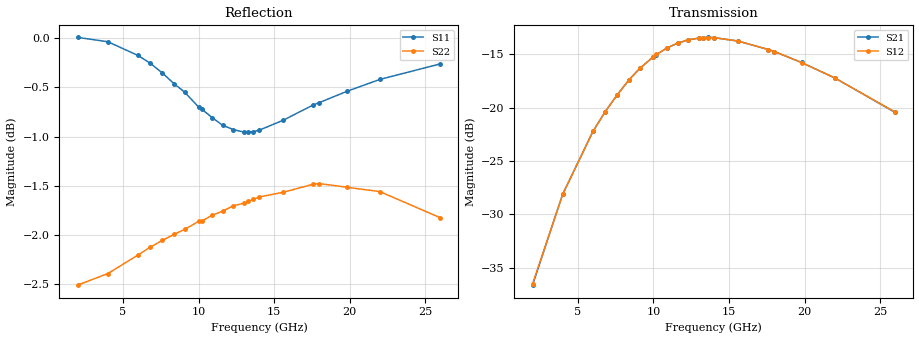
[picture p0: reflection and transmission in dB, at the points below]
! CHUO DENSHI KOGYO Co.,Ltd.
! 1. March 2016
! CKRF7513MM34
! N-channel HJ-FET
! Vds = 0 V Vgs = 0 V
# Hz S  MA  R 50
!  f  S11  S21  S12  S22
!  Hz  MAG  ANG  MAG  ANG  MAG  ANG  MAG  ANG
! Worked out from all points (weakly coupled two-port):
!   241 points, 2 GHz to 26 GHz, reference 50 ohm
!   highest |S21| = -13.42 dB at 13.6 GHz (marker M1); lowest = -36.6 dB at 2 GHz (marker M2)
!   lowest |S11| = -1.0 dB at 13 GHz (marker M3), VSWR 18.22, Z = 2.85 + j10 ohm
!   |S11| at or under -10 dB: nowhere
!   |S22| runs from -2.5 to -1.5 dB; largest |S21 - S12| = 0.001
!   S11 on the Smith chart (normalised r, x): 2 GHz: -0.02, -5.58; 6.8 GHz: 0.03, -1.17; 10.2 GHz: 0.05, -0.32; 13.3 GHz: 0.06, +0.25; 17.6 GHz: 0.08, +1.05; 26 GHz: 0.33, +4.53
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2e9  1.001 -20.3  0.01476 99.0  0.01497 99.3  0.7489 154.7
4e9  0.9959 -42.6  0.03941 95.8  0.03936 95.8  0.7591 131.3
6e9  0.98 -68.8  0.07735 83.2  0.07749 83.0  0.7758 109.8
6.8e9  0.9712 -81.0  0.09561 75.4  0.09542 75.4  0.7829 101.8
7.6e9  0.9602 -94.2  0.1147 67.4  0.1146 67.4  0.7891 94.3
8.4e9  0.9479 -108.4  0.1353 58.8  0.1354 58.8  0.7949 87.0
9.1e9  0.9386 -121.9  0.1525 50.3  0.1526 50.3  0.7995 80.9
1e10  0.9226 -140.1  0.1731 38.9  0.1735 39.0  0.8069 73.4
1.02e10  0.9205 -144.2  0.177 36.4  0.1775 36.5  0.8071 71.9
1.09e10  0.9113 -159.2  0.1903 27.4  0.1902 27.4  0.8127 66.4
1.16e10  0.903 -174.1  0.2001 18.5  0.2006 18.5  0.8167 61.0
1.23e10  0.8986 171.4  0.2075 9.6  0.2077 9.7  0.8218 55.8
1.3e10  0.8959 157.3  0.2116 0.9  0.2114 1.0  0.8243 50.8
1.33e10  0.896 151.6  0.2126 -2.7  0.2125 -2.6  0.8261 48.6
1.36e10  0.8964 145.9  0.2132 -6.2  0.2129 -6.1  0.8279 46.5
1.4e10  0.8978 138.7  0.2127 -11.0  0.2126 -10.8  0.8303 43.7
1.56e10  0.9084 112.8  0.2049 -28.0  0.205 -27.9  0.8349 32.6
1.76e10  0.9249 87.0  0.1871 -46.5  0.1871 -46.4  0.8429 19.4
1.8e10  0.9274 82.6  0.1829 -49.9  0.1831 -49.7  0.8435 16.7
1.98e10  0.9396 65.4  0.1627 -63.9  0.1626 -63.8  0.8399 5.1
2.2e10  0.9529 48.6  0.1377 -79.3  0.1377 -79.2  0.8356 -8.9
2.6e10  0.9704 24.8  0.09489 -106.0  0.09529 -105.8  0.8104 -33.2
